VERSION 5.7 ;
  NOWIREEXTENSIONATPIN ON ;
  DIVIDERCHAR "/" ;
  BUSBITCHARS "[]" ;
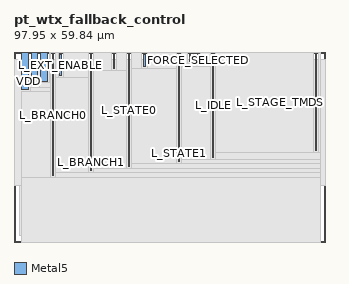
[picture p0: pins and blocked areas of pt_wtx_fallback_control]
MACRO pt_wtx_fallback_control
  CLASS BLOCK ;
  FOREIGN pt_wtx_fallback_control ;
  ORIGIN -1.500 0.000 ;
  SIZE 97.950 BY 59.840 ;
  PIN L_BRANCH0
    DIRECTION INPUT ;
    USE SIGNAL ;
    ANTENNAGATEAREA 1.680000 ;
    PORT
      LAYER Metal5 ;
        RECT 13.580 20.930 14.020 59.060 ;
    END
  END L_BRANCH0
  PIN L_BRANCH1
    DIRECTION INPUT ;
    USE SIGNAL ;
    ANTENNAGATEAREA 2.240000 ;
    PORT
      LAYER Metal5 ;
        RECT 25.580 22.370 26.020 59.060 ;
    END
  END L_BRANCH1
  PIN L_STATE0
    DIRECTION INPUT ;
    USE SIGNAL ;
    ANTENNAGATEAREA 1.680000 ;
    PORT
      LAYER Metal5 ;
        RECT 37.580 23.810 38.020 59.060 ;
    END
  END L_STATE0
  PIN L_STATE1
    DIRECTION INPUT ;
    USE SIGNAL ;
    ANTENNAGATEAREA 2.240000 ;
    PORT
      LAYER Metal5 ;
        RECT 53.180 25.250 53.620 59.060 ;
    END
  END L_STATE1
  PIN L_IDLE
    DIRECTION INPUT ;
    USE SIGNAL ;
    ANTENNAGATEAREA 1.680000 ;
    PORT
      LAYER Metal5 ;
        RECT 63.980 26.690 64.420 59.060 ;
    END
  END L_IDLE
  PIN L_STAGE_TMDS
    DIRECTION INPUT ;
    USE SIGNAL ;
    ANTENNAGATEAREA 2.240000 ;
    PORT
      LAYER Metal5 ;
        RECT 96.380 28.850 96.820 59.060 ;
    END
  END L_STAGE_TMDS
  PIN L_EXT_ENABLE
    DIRECTION INPUT ;
    USE SIGNAL ;
    ANTENNAGATEAREA 2.240000 ;
    PORT
      LAYER Metal5 ;
        RECT 15.980 52.420 16.420 59.060 ;
    END
  END L_EXT_ENABLE
  PIN ISO_wired
    DIRECTION INPUT ;
    USE SIGNAL ;
    ANTENNAGATEAREA 1.680000 ;
    PORT
      LAYER Metal5 ;
        RECT 42.380 55.300 42.820 59.060 ;
    END
  END ISO_wired
  PIN FORCE_LEAF
    DIRECTION INPUT ;
    USE SIGNAL ;
    ANTENNAGATEAREA 2.240000 ;
    PORT
      LAYER Metal5 ;
        RECT 56.780 56.740 57.220 59.060 ;
    END
  END FORCE_LEAF
  PIN TMDS_REQUEST
    DIRECTION OUTPUT ;
    USE SIGNAL ;
    ANTENNADIFFAREA 2.910000 ;
    PORT
      LAYER Metal5 ;
        RECT 32.780 54.580 33.220 59.060 ;
    END
  END TMDS_REQUEST
  PIN WIRED_ON
    DIRECTION OUTPUT ;
    USE SIGNAL ;
    ANTENNAGATEAREA 2.240000 ;
    ANTENNADIFFAREA 2.910000 ;
    PORT
      LAYER Metal5 ;
        RECT 57.980 56.020 58.420 59.060 ;
    END
  END WIRED_ON
  PIN FORCE_SELECTED
    DIRECTION OUTPUT ;
    USE SIGNAL ;
    ANTENNADIFFAREA 2.910000 ;
    PORT
      LAYER Metal5 ;
        RECT 59.180 57.460 59.620 59.060 ;
    END
  END FORCE_SELECTED
  PIN RAIL_wired
    DIRECTION INOUT ;
    USE POWER ;
    PORT
      LAYER Metal5 ;
        RECT 10.000 50.680 12.000 59.840 ;
    END
  END RAIL_wired
  PIN VDD
    DIRECTION INOUT ;
    USE POWER ;
    PORT
      LAYER Metal5 ;
        RECT 4.000 48.040 6.000 59.840 ;
    END
  END VDD
  PIN VSS
    DIRECTION INOUT ;
    USE GROUND ;
    PORT
      LAYER Metal5 ;
        RECT 7.000 49.360 9.000 59.840 ;
    END
  END VSS
  OBS
      LAYER Nwell ;
        RECT 4.800 7.350 92.050 46.500 ;
      LAYER Metal1 ;
        RECT 5.100 2.000 94.340 45.900 ;
      LAYER Metal2 ;
        RECT 3.300 2.100 97.650 45.800 ;
      LAYER Metal3 ;
        RECT 3.300 2.100 97.650 57.520 ;
      LAYER Metal4 ;
        RECT 1.500 17.950 99.450 57.520 ;
      LAYER Metal5 ;
        RECT 12.600 59.660 98.020 59.840 ;
        RECT 12.600 50.080 12.980 59.660 ;
        RECT 9.600 48.760 12.980 50.080 ;
        RECT 6.600 47.440 12.980 48.760 ;
        RECT 4.000 20.330 12.980 47.440 ;
        RECT 14.620 51.820 15.380 59.660 ;
        RECT 17.020 51.820 24.980 59.660 ;
        RECT 14.620 21.770 24.980 51.820 ;
        RECT 26.620 53.980 32.180 59.660 ;
        RECT 33.820 53.980 36.980 59.660 ;
        RECT 26.620 23.210 36.980 53.980 ;
        RECT 38.620 54.700 41.780 59.660 ;
        RECT 43.420 54.700 52.580 59.660 ;
        RECT 38.620 24.650 52.580 54.700 ;
        RECT 54.220 56.140 56.180 59.660 ;
        RECT 60.220 56.860 63.380 59.660 ;
        RECT 54.220 55.420 57.380 56.140 ;
        RECT 59.020 55.420 63.380 56.860 ;
        RECT 54.220 26.090 63.380 55.420 ;
        RECT 65.020 28.250 95.780 59.660 ;
        RECT 97.420 28.250 98.020 59.660 ;
        RECT 65.020 26.090 98.020 28.250 ;
        RECT 54.220 24.650 98.020 26.090 ;
        RECT 38.620 23.210 98.020 24.650 ;
        RECT 26.620 21.770 98.020 23.210 ;
        RECT 14.620 20.330 98.020 21.770 ;
        RECT 4.000 0.000 98.020 20.330 ;
  END
END pt_wtx_fallback_control
END LIBRARY

